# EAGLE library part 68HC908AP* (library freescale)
8-bit microcontroller units (MCUs) low-cost, high-performance M68HC08 Family Source: http://www.freescale.com/files/microcontrollers/doc/data_sheet/MC68HC908AP64.pdf

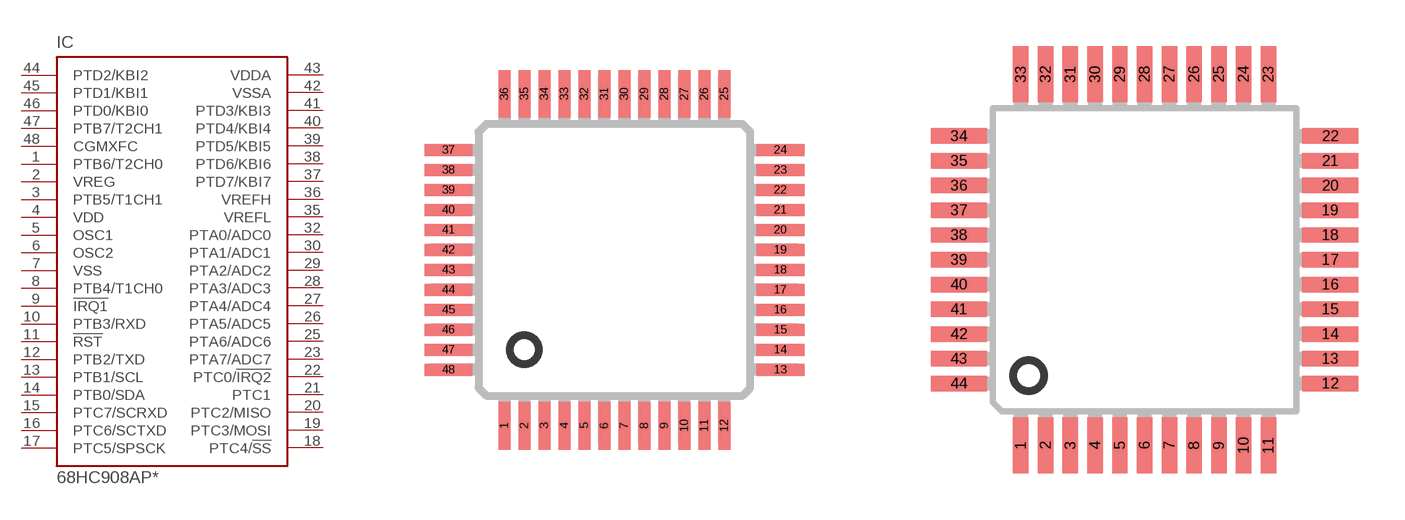
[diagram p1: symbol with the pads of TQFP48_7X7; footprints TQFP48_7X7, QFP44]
Designator prefix IC

## 68HC908AP8CFA (MF: MOTOROLA; MPN: MC68HC908AP8CFA; OC_FARNELL: unknown; OC_NEWARK: 88H9992), 68HC908AP16CFA (MF: MOTOROLA; MPN: MC68HC908AP16CFA; OC_FARNELL: unknown; OC_NEWARK: 88H9989), 68HC908AP32CFA (MF: MOTOROLA; MPN: MC68HC908AP32CFA; OC_FARNELL: unknown; OC_NEWARK: 86H4494), 68HC908AP64CFA (MF: MOTOROLA; MPN: MC68HC908AP64CFA; OC_FARNELL: unknown; OC_NEWARK: 86H4497)  [TQFP48_7X7]
1  PTB6/T2CH0
2  VREG  out
3  PTB5/T1CH1
4  VDD  pwr
5  OSC1  in
6  OSC2  out
7  VSS  pwr
8  PTB4/T1CH0
9  !IRQ1  in
10  PTB3/RXD
11  !RST  in
12  PTB2/TXD
13  PTB1/SCL
14  PTB0/SDA
15  PTC7/SCRXD
16  PTC6/SCTXD
17  PTC5/SPSCK
18  PTC4/!SS
19  PTC3/MOSI
20  PTC2/MISO
21  PTC1
22  PTC0/!IRQ2
23  PTA7/ADC7
25  PTA6/ADC6
26  PTA5/ADC5
27  PTA4/ADC4
28  PTA3/ADC3
29  PTA2/ADC2
30  PTA1/ADC1
32  PTA0/ADC0
35  VREFL  pas
36  VREFH  pas
37  PTD7/KBI7
38  PTD6/KBI6
39  PTD5/KBI5
40  PTD4/KBI4
41  PTD3/KBI3
42  VSSA  pwr
43  VDDA  pwr
44  PTD2/KBI2
45  PTD1/KBI1
46  PTD0/KBI0
47  PTB7/T2CH1
48  CGMXFC  in

## 68HC908AP8CFB (MF: MOTOROLA; MPN: MC68HC908AP8CFB; OC_FARNELL: unknown; OC_NEWARK: 88H9993), 68HC908AP16CFB (MF: MOTOROLA; MPN: MC68HC908AP16CFB; OC_FARNELL: unknown; OC_NEWARK: 88H9990), 68HC908AP23CFB (OC_FARNELL: unknown; OC_NEWARK: unknown), 68HC908AP64CFB (MF: MOTOROLA; MPN: MC68HC908AP64CFB; OC_FARNELL: unknown; OC_NEWARK: 86H4498)  [QFP44]
1  PTB6/T2CH0
2  VREG  out
3  PTB5/T1CH1
4  VDD  pwr
5  OSC1  in
6  OSC2  out
7  VSS  pwr
8  PTB4/T1CH0
9  !IRQ1  in
10  PTB3/RXD
11  !RST  in
12  PTB2/TXD
13  PTB1/SCL
14  PTB0/SDA
15  PTC7/SCRXD
16  PTC6/SCTXD
17  PTC5/SPSCK
18  PTC4/!SS
19  PTC3/MOSI
20  PTC2/MISO
21  PTC1
22  PTC0/!IRQ2
23  PTA7/ADC7
24  PTA6/ADC6
25  PTA5/ADC5
26  PTA4/ADC4
27  PTA3/ADC3
28  PTA2/ADC2
29  PTA1/ADC1
30  PTA0/ADC0
31  VREFL  pas
32  VREFH  pas
33  PTD7/KBI7
34  PTD6/KBI6
35  PTD5/KBI5
36  PTD4/KBI4
37  PTD3/KBI3
38  VSSA  pwr
39  VDDA  pwr
40  PTD2/KBI2
41  PTD1/KBI1
42  PTD0/KBI0
43  PTB7/T2CH1
44  CGMXFC  in

## Footprint TQFP48_7X7 (pad centres in mm)
48-Pin LQFP (Case #932) Source: http://www.freescale.com/files/microcontrollers/doc/data_sheet/MC68HC908AP64.pdf
smd 0.3 x 1.2: 1 -2.75,-4.15; 2 -2.25,-4.15; 3 -1.75,-4.15; 4 -1.25,-4.15; 5 -0.75,-4.15; 6 -0.25,-4.15; 7 0.25,-4.15; 8 0.75,-4.15; 9 1.25,-4.15; 10 1.75,-4.15; 11 2.25,-4.15; 12 2.75,-4.15; 25 2.75,4.15; 26 2.25,4.15; 27 1.75,4.15; 28 1.25,4.15; 29 0.75,4.15; 30 0.25,4.15; 31 -0.25,4.15; 32 -0.75,4.15; 33 -1.25,4.15; 34 -1.75,4.15; 35 -2.25,4.15; 36 -2.75,4.15
smd 1.2 x 0.3: 13 4.15,-2.75; 14 4.15,-2.25; 15 4.15,-1.75; 16 4.15,-1.25; 17 4.15,-0.75; 18 4.15,-0.25; 19 4.15,0.25; 20 4.15,0.75; 21 4.15,1.25; 22 4.15,1.75; 23 4.15,2.25; 24 4.15,2.75; 37 -4.15,2.75; 38 -4.15,2.25; 39 -4.15,1.75; 40 -4.15,1.25; 41 -4.15,0.75; 42 -4.15,0.25; 43 -4.15,-0.25; 44 -4.15,-0.75; 45 -4.15,-1.25; 46 -4.15,-1.75; 47 -4.15,-2.25; 48 -4.15,-2.75

## Footprint QFP44 (pad centres in mm)
44-Pin QFP (Case #824A) Source: http://www.freescale.com/files/microcontrollers/doc/data_sheet/MC68HC908AP64.pdf
smd 0.5 x 1.8: 1 -4,-6; 2 -3.2,-6; 3 -2.4,-6; 4 -1.6,-6; 5 -0.8,-6; 6 0,-6; 7 0.8,-6; 8 1.6,-6; 9 2.4,-6; 10 3.2,-6; 11 4,-6; 23 4,6; 24 3.2,6; 25 2.4,6; 26 1.6,6; 27 0.8,6; 28 0,6; 29 -0.8,6; 30 -1.6,6; 31 -2.4,6; 32 -3.2,6; 33 -4,6
smd 1.8 x 0.5: 12 6,-4; 13 6,-3.2; 14 6,-2.4; 15 6,-1.6; 16 6,-0.8; 17 6,0; 18 6,0.8; 19 6,1.6; 20 6,2.4; 21 6,3.2; 22 6,4; 34 -6,4; 35 -6,3.2; 36 -6,2.4; 37 -6,1.6; 38 -6,0.8; 39 -6,0; 40 -6,-0.8; 41 -6,-1.6; 42 -6,-2.4; 43 -6,-3.2; 44 -6,-4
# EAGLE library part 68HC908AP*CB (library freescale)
8-bit microcontroller units (MCUs) low-cost, high-performance M68HC08 Family Source: http://www.freescale.com/files/microcontrollers/doc/data_sheet/MC68HC908AP64.pdf

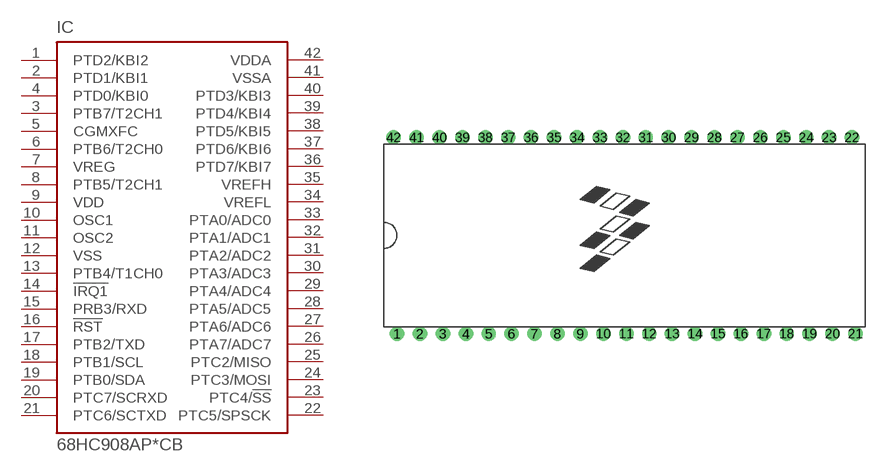
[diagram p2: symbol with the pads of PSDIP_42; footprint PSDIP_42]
Designator prefix IC

## 68HC908AP8CB (MF: MOTOROLA; MPN: MC68HC908AP8CB; OC_FARNELL: unknown; OC_NEWARK: 88H9991), 68HC908AP16CB (MF: MOTOROLA; MPN: MC68HC908AP16CB; OC_FARNELL: unknown; OC_NEWARK: 88H9988), 68HC908AP32CB (MF: MOTOROLA; MPN: MC68HC908AP32CB; OC_FARNELL: unknown; OC_NEWARK: 86H4493), 68HC908AP64CB (MF: MOTOROLA; MPN: MC68HC908AP64CB; OC_FARNELL: unknown; OC_NEWARK: 86H4496)  [PSDIP_42]
1  PTD2/KBI2
2  PTD1/KBI1
3  PTB7/T2CH1
4  PTD0/KBI0
5  CGMXFC  in
6  PTB6/T2CH0
7  VREG  out
8  PTB5/T2CH1
9  VDD  pwr
10  OSC1  in
11  OSC2  out
12  VSS  pwr
13  PTB4/T1CH0
14  !IRQ1  in
15  PRB3/RXD
16  !RST  in
17  PTB2/TXD
18  PTB1/SCL
19  PTB0/SDA
20  PTC7/SCRXD
21  PTC6/SCTXD
22  PTC5/SPSCK
23  PTC4/!SS
24  PTC3/MOSI
25  PTC2/MISO
26  PTA7/ADC7
27  PTA6/ADC6
28  PTA5/ADC5
29  PTA4/ADC4
30  PTA3/ADC3
31  PTA2/ADC2
32  PTA1/ADC1
33  PTA0/ADC0
34  VREFL  pas
35  VREFH  pas
36  PTD7/KBI7
37  PTD6/KBI6
38  PTD5/KBI5
39  PTD4/KBI4
40  PTD3/KBI3
41  VSSA  pwr
42  VDDA  pwr

## Footprint PSDIP_42 (pad centres in mm)
42-Pin Shrink Dual In-Line Package (SDIP) Case #858 Source: http://www.freescale.com/files/microcontrollers/doc/data_sheet/MC68HC908AP64.pdf
drill 0.61 pad 1.016 round: 1 -17.78,-7.62; 2 -16.002,-7.62; 3 -14.224,-7.62; 4 -12.446,-7.62; 5 -10.668,-7.62; 6 -8.89,-7.62; 7 -7.112,-7.62; 8 -5.334,-7.62; 9 -3.556,-7.62; 10 -1.778,-7.62; 11 0,-7.62; 12 1.778,-7.62; 13 3.556,-7.62; 14 5.334,-7.62; 15 7.112,-7.62; 16 8.89,-7.62; 17 10.668,-7.62; 18 12.446,-7.62; 19 14.224,-7.62; 20 16.002,-7.62; 21 17.78,-7.62; 22 17.513,7.62; 23 15.735,7.62; 24 13.957,7.62; 25 12.179,7.62; 26 10.401,7.62; 27 8.623,7.62; 28 6.845,7.62; 29 5.067,7.62; 30 3.289,7.62; 31 1.511,7.62; 32 -0.267,7.62; 33 -2.045,7.62; 34 -3.823,7.62; 35 -5.601,7.62; 36 -7.379,7.62; 37 -9.157,7.62; 38 -10.935,7.62; 39 -12.713,7.62; 40 -14.491,7.62; 41 -16.269,7.62; 42 -18.047,7.62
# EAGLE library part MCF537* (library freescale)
MCF537x ColdFire® Microprocessor Source: www.freescale.com .. MCF5373DS.pdf

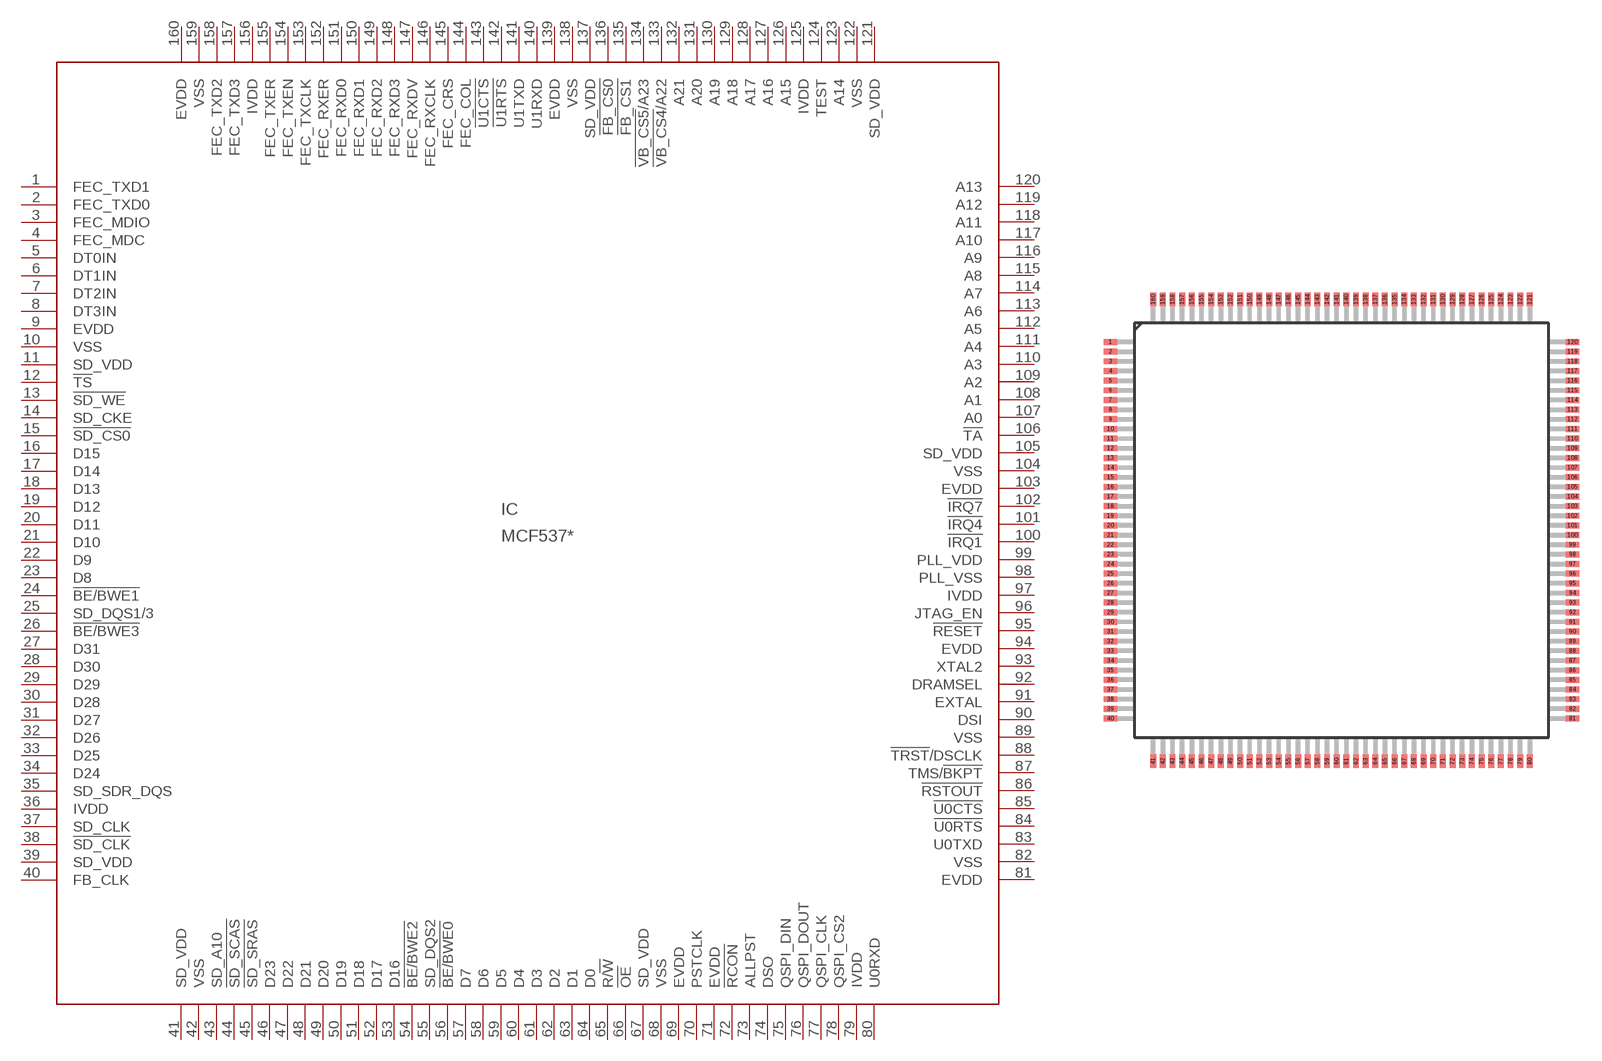
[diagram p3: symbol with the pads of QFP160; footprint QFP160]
Designator prefix IC

## MCF5372 (OC_FARNELL: unknown; OC_NEWARK: unknown), MCF5373 (OC_FARNELL: unknown; OC_NEWARK: unknown)  [QFP160]
1  FEC_TXD1  out
2  FEC_TXD0  out
3  FEC_MDIO
4  FEC_MDC  out
5  DT0IN  in
6  DT1IN  in
7  DT2IN  in
8  DT3IN  in
9  EVDD  pwr
10  VSS  pwr
11  SD_VDD  pwr
12  !TS  out
13  !SD_WE  out
14  SD_CKE  out
15  !SD_CS0  out
16  D15
17  D14
18  D13
19  D12
20  D11
21  D10
22  D9
23  D8
24  !BE/BWE1  out
25  SD_DQS1/3  out
26  !BE/BWE3  out
27  D31
28  D30
29  D29
30  D28
31  D27
32  D26
33  D25
34  D24
35  SD_SDR_DQS  out
36  IVDD  pwr
37  SD_CLK  out
38  !SD_CLK  out
39  SD_VDD  pwr
40  FB_CLK  out
41  SD_VDD  pwr
42  VSS  pwr
43  SD_A10  out
44  !SD_SCAS  out
45  !SD_SRAS  out
46  D23
47  D22
48  D21
49  D20
50  D19
51  D18
52  D17
53  D16
54  !BE/BWE2  out
55  SD_DQS2  out
56  !BE/BWE0  out
57  D7
58  D6
59  D5
60  D4
61  D3
62  D2
63  D1
64  D0
65  R/!W  out
66  !OE  out
67  SD_VDD  pwr
68  VSS  pwr
69  EVDD  pwr
70  PSTCLK  out
71  EVDD  pwr
72  !RCON  in
73  ALLPST  out
74  DSO  out
75  QSPI_DIN  in
76  QSPI_DOUT  out
77  QSPI_CLK  out
78  QSPI_CS2  out
79  IVDD  pwr
80  U0RXD  in
81  EVDD  pwr
82  VSS  pwr
83  U0TXD  out
84  !U0RTS  out
85  !U0CTS  in
86  !RSTOUT  out
87  TMS/!BKPT  in
88  !TRST!/DSCLK  in
89  VSS  pwr
90  DSI  in
91  EXTAL  in
92  DRAMSEL  in
93  XTAL2  out
94  EVDD  pwr
95  !RESET  in
96  JTAG_EN  in
97  IVDD  pwr
98  PLL_VSS  pwr
99  PLL_VDD  pwr
100  !IRQ1  in
101  !IRQ4  in
102  !IRQ7  in
103  EVDD  pwr
104  VSS  pwr
105  SD_VDD  pwr
106  !TA  in
107  A0  out
108  A1  out
109  A2  out
110  A3  out
111  A4  out
112  A5  out
113  A6  out
114  A7  out
115  A8  out
116  A9  out
117  A10  out
118  A11  out
119  A12  out
120  A13  out
121  SD_VDD  pwr
122  VSS  pwr
123  A14  out
124  TEST  in
125  IVDD  pwr
126  A15  out
127  A16  out
128  A17  out
129  A18  out
130  A19  out
131  A20  out
132  A21  out
133  !VB_CS4!/A22  out
134  !VB_CS5!/A23  out
135  !FB_CS1  out
136  !FB_CS0  out
137  SD_VDD  pwr
138  VSS  pwr
139  EVDD  pwr
140  U1RXD  in
141  U1TXD  out
142  !U1RTS  out
143  !U1CTS  in
144  FEC_COL  in
145  FEC_CRS  in
146  FEC_RXCLK  in
147  FEC_RXDV  in
148  FEC_RXD3  in
149  FEC_RXD2  in
150  FEC_RXD1  in
151  FEC_RXD0  in
152  FEC_RXER  in
153  FEC_TXCLK  in
154  FEC_TXEN  out
155  FEC_TXER  out
156  IVDD  pwr
157  FEC_TXD3  out
158  FEC_TXD2  out
159  VSS  pwr
160  EVDD  pwr

## Footprint QFP160 (pad centres in mm)
QFP160 Auto generated by make-symbol-device-package-bsdl.ulp Rev. 22
smd 0.9 x 0.4: 1 -15.55,12.675; 2 -15.55,12.025; 3 -15.55,11.375; 4 -15.55,10.725; 5 -15.55,10.075; 6 -15.55,9.425; 7 -15.55,8.775; 8 -15.55,8.125; 9 -15.55,7.475; 10 -15.55,6.825; 11 -15.55,6.175; 12 -15.55,5.525; 13 -15.55,4.875; 14 -15.55,4.225; 15 -15.55,3.575; 16 -15.55,2.925; 17 -15.55,2.275; 18 -15.55,1.625; 19 -15.55,0.975; 20 -15.55,0.325; 21 -15.55,-0.325; 22 -15.55,-0.975; 23 -15.55,-1.625; 24 -15.55,-2.275; 25 -15.55,-2.925; 26 -15.55,-3.575; 27 -15.55,-4.225; 28 -15.55,-4.875; 29 -15.55,-5.525; 30 -15.55,-6.175; 31 -15.55,-6.825; 32 -15.55,-7.475; 33 -15.55,-8.125; 34 -15.55,-8.775; 35 -15.55,-9.425; 36 -15.55,-10.075; 37 -15.55,-10.725; 38 -15.55,-11.375; 39 -15.55,-12.025; 40 -15.55,-12.675; 81 15.55,-12.675; 82 15.55,-12.025; 83 15.55,-11.375; 84 15.55,-10.725; 85 15.55,-10.075; 86 15.55,-9.425; 87 15.55,-8.775; 88 15.55,-8.125; 89 15.55,-7.475; 90 15.55,-6.825; 91 15.55,-6.175; 92 15.55,-5.525; 93 15.55,-4.875; 94 15.55,-4.225; 95 15.55,-3.575; 96 15.55,-2.925; 97 15.55,-2.275; 98 15.55,-1.625; 99 15.55,-0.975; 100 15.55,-0.325; 101 15.55,0.325; 102 15.55,0.975; 103 15.55,1.625; 104 15.55,2.275; 105 15.55,2.925; 106 15.55,3.575; 107 15.55,4.225; 108 15.55,4.875; 109 15.55,5.525; 110 15.55,6.175; 111 15.55,6.825; 112 15.55,7.475; 113 15.55,8.125; 114 15.55,8.775; 115 15.55,9.425; 116 15.55,10.075; 117 15.55,10.725; 118 15.55,11.375; 119 15.55,12.025; 120 15.55,12.675
smd 0.4 x 0.9: 41 -12.675,-15.55; 42 -12.025,-15.55; 43 -11.375,-15.55; 44 -10.725,-15.55; 45 -10.075,-15.55; 46 -9.425,-15.55; 47 -8.775,-15.55; 48 -8.125,-15.55; 49 -7.475,-15.55; 50 -6.825,-15.55; 51 -6.175,-15.55; 52 -5.525,-15.55; 53 -4.875,-15.55; 54 -4.225,-15.55; 55 -3.575,-15.55; 56 -2.925,-15.55; 57 -2.275,-15.55; 58 -1.625,-15.55; 59 -0.975,-15.55; 60 -0.325,-15.55; 61 0.325,-15.55; 62 0.975,-15.55; 63 1.625,-15.55; 64 2.275,-15.55; 65 2.925,-15.55; 66 3.575,-15.55; 67 4.225,-15.55; 68 4.875,-15.55; 69 5.525,-15.55; 70 6.175,-15.55; 71 6.825,-15.55; 72 7.475,-15.55; 73 8.125,-15.55; 74 8.775,-15.55; 75 9.425,-15.55; 76 10.075,-15.55; 77 10.725,-15.55; 78 11.375,-15.55; 79 12.025,-15.55; 80 12.675,-15.55; 121 12.675,15.55; 122 12.025,15.55; 123 11.375,15.55; 124 10.725,15.55; 125 10.075,15.55; 126 9.425,15.55; 127 8.775,15.55; 128 8.125,15.55; 129 7.475,15.55; 130 6.825,15.55; 131 6.175,15.55; 132 5.525,15.55; 133 4.875,15.55; 134 4.225,15.55; 135 3.575,15.55; 136 2.925,15.55; 137 2.275,15.55; 138 1.625,15.55; 139 0.975,15.55; 140 0.325,15.55; 141 -0.325,15.55; 142 -0.975,15.55; 143 -1.625,15.55; 144 -2.275,15.55; 145 -2.925,15.55; 146 -3.575,15.55; 147 -4.225,15.55; 148 -4.875,15.55; 149 -5.525,15.55; 150 -6.175,15.55; 151 -6.825,15.55; 152 -7.475,15.55; 153 -8.125,15.55; 154 -8.775,15.55; 155 -9.425,15.55; 156 -10.075,15.55; 157 -10.725,15.55; 158 -11.375,15.55; 159 -12.025,15.55; 160 -12.675,15.55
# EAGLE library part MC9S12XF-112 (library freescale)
MC9S12XF512 Source: www.freescale.com .. MC9S12XF512V1RM.pdf

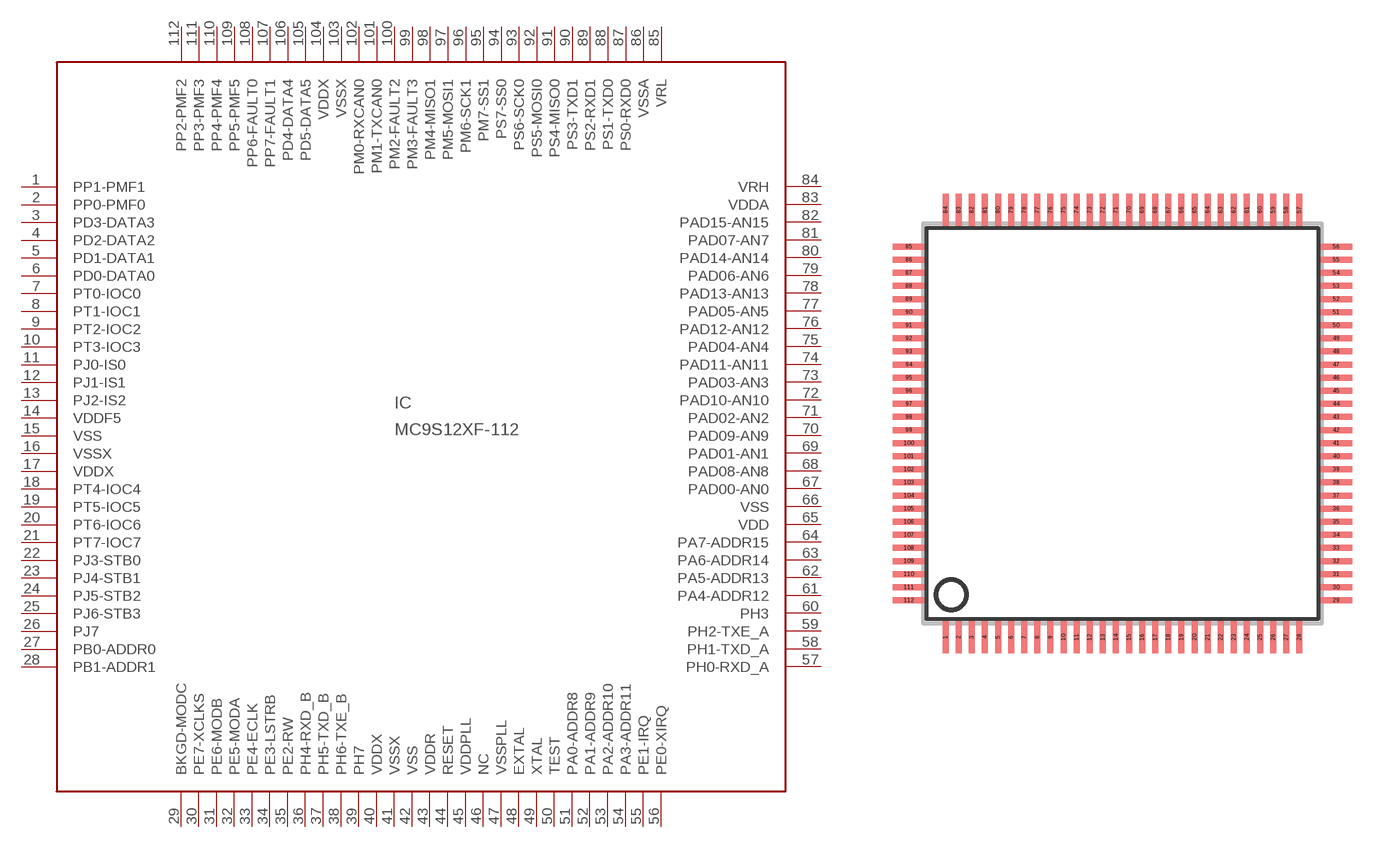
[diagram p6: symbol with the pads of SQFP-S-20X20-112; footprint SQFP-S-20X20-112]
Designator prefix IC

## MC9S12XF-112 (OC_FARNELL: unknown; OC_NEWARK: unknown)  [SQFP-S-20X20-112]
1  PP1-PMF1
2  PP0-PMF0
3  PD3-DATA3
4  PD2-DATA2
5  PD1-DATA1
6  PD0-DATA0
7  PT0-IOC0
8  PT1-IOC1
9  PT2-IOC2
10  PT3-IOC3
11  PJ0-IS0
12  PJ1-IS1
13  PJ2-IS2
14  VDDF5  pwr
15  VSS  pwr
16  VSSX  pwr
17  VDDX  pwr
18  PT4-IOC4
19  PT5-IOC5
20  PT6-IOC6
21  PT7-IOC7
22  PJ3-STB0
23  PJ4-STB1
24  PJ5-STB2
25  PJ6-STB3
26  PJ7
27  PB0-ADDR0
28  PB1-ADDR1
29  BKGD-MODC
30  PE7-XCLKS
31  PE6-MODB
32  PE5-MODA
33  PE4-ECLK
34  PE3-LSTRB
35  PE2-RW
36  PH4-RXD_B
37  PH5-TXD_B
38  PH6-TXE_B
39  PH7
40  VDDX  pwr
41  VSSX  pwr
42  VSS  pwr
43  VDDR  pwr
44  RESET
45  VDDPLL  pwr
46  NC  nc
47  VSSPLL  pwr
48  EXTAL  pas
49  XTAL  pas
50  TEST  in
51  PA0-ADDR8
52  PA1-ADDR9
53  PA2-ADDR10
54  PA3-ADDR11
55  PE1-IRQ  in
56  PE0-XIRQ  in
57  PH0-RXD_A
58  PH1-TXD_A
59  PH2-TXE_A
60  PH3
61  PA4-ADDR12
62  PA5-ADDR13
63  PA6-ADDR14
64  PA7-ADDR15
65  VDD  pwr
66  VSS  pwr
67  PAD00-AN0
68  PAD08-AN8
69  PAD01-AN1
70  PAD09-AN9
71  PAD02-AN2
72  PAD10-AN10
73  PAD03-AN3
74  PAD11-AN11
75  PAD04-AN4
76  PAD12-AN12
77  PAD05-AN5
78  PAD13-AN13
79  PAD06-AN6
80  PAD14-AN14
81  PAD07-AN7
82  PAD15-AN15
83  VDDA  pwr
84  VRH  pwr
85  VRL  pwr
86  VSSA  pwr
87  PS0-RXD0
88  PS1-TXD0
89  PS2-RXD1
90  PS3-TXD1
91  PS4-MISO0
92  PS5-MOSI0
93  PS6-SCK0
94  PS7-SS0
95  PM7-SS1
96  PM6-SCK1
97  PM5-MOSI1
98  PM4-MISO1
99  PM3-FAULT3
100  PM2-FAULT2
101  PM1-TXCAN0
102  PM0-RXCAN0
103  VSSX  pwr
104  VDDX  pwr
105  PD5-DATA5
106  PD4-DATA4
107  PP7-FAULT1
108  PP6-FAULT0
109  PP5-PMF5
110  PP4-PMF4
111  PP3-PMF3
112  PP2-PMF2

## Footprint SQFP-S-20X20-112 (pad centres in mm)
LQFP112 20x20mm 112-Pin LQFP Mechanical Dimensions (Case No. 987) Source: www.freescale.com .. MC9S12XF512V1RM.pdf
smd 0.3 x 1.6: 1 -8.775,-10.6; 2 -8.125,-10.6; 3 -7.475,-10.6; 4 -6.825,-10.6; 5 -6.175,-10.6; 6 -5.525,-10.6; 7 -4.875,-10.6; 8 -4.225,-10.6; 9 -3.575,-10.6; 10 -2.925,-10.6; 11 -2.275,-10.6; 12 -1.625,-10.6; 13 -0.975,-10.6; 14 -0.325,-10.6; 15 0.325,-10.6; 16 0.975,-10.6; 17 1.625,-10.6; 18 2.275,-10.6; 19 2.925,-10.6; 20 3.575,-10.6; 21 4.225,-10.6; 22 4.875,-10.6; 23 5.525,-10.6; 24 6.175,-10.6; 25 6.825,-10.6; 26 7.475,-10.6; 27 8.125,-10.6; 28 8.775,-10.6; 57 8.775,10.6; 58 8.125,10.6; 59 7.475,10.6; 60 6.825,10.6; 61 6.175,10.6; 62 5.525,10.6; 63 4.875,10.6; 64 4.225,10.6; 65 3.575,10.6; 66 2.925,10.6; 67 2.275,10.6; 68 1.625,10.6; 69 0.975,10.6; 70 0.325,10.6; 71 -0.325,10.6; 72 -0.975,10.6; 73 -1.625,10.6; 74 -2.275,10.6; 75 -2.925,10.6; 76 -3.575,10.6; 77 -4.225,10.6; 78 -4.875,10.6; 79 -5.525,10.6; 80 -6.175,10.6; 81 -6.825,10.6; 82 -7.475,10.6; 83 -8.125,10.6; 84 -8.775,10.6
smd 1.6 x 0.3: 29 10.6,-8.775; 30 10.6,-8.125; 31 10.6,-7.475; 32 10.6,-6.825; 33 10.6,-6.175; 34 10.6,-5.525; 35 10.6,-4.875; 36 10.6,-4.225; 37 10.6,-3.575; 38 10.6,-2.925; 39 10.6,-2.275; 40 10.6,-1.625; 41 10.6,-0.975; 42 10.6,-0.325; 43 10.6,0.325; 44 10.6,0.975; 45 10.6,1.625; 46 10.6,2.275; 47 10.6,2.925; 48 10.6,3.575; 49 10.6,4.225; 50 10.6,4.875; 51 10.6,5.525; 52 10.6,6.175; 53 10.6,6.825; 54 10.6,7.475; 55 10.6,8.125; 56 10.6,8.775; 85 -10.6,8.775; 86 -10.6,8.125; 87 -10.6,7.475; 88 -10.6,6.825; 89 -10.6,6.175; 90 -10.6,5.525; 91 -10.6,4.875; 92 -10.6,4.225; 93 -10.6,3.575; 94 -10.6,2.925; 95 -10.6,2.275; 96 -10.6,1.625; 97 -10.6,0.975; 98 -10.6,0.325; 99 -10.6,-0.325; 100 -10.6,-0.975; 101 -10.6,-1.625; 102 -10.6,-2.275; 103 -10.6,-2.925; 104 -10.6,-3.575; 105 -10.6,-4.225; 106 -10.6,-4.875; 107 -10.6,-5.525; 108 -10.6,-6.175; 109 -10.6,-6.825; 110 -10.6,-7.475; 111 -10.6,-8.125; 112 -10.6,-8.775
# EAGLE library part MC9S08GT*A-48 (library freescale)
HCS08 Microcontroller Source: http://www.freescale.com/files/microcontrollers/doc/data_sheet/MC9S08GT16A.pdf

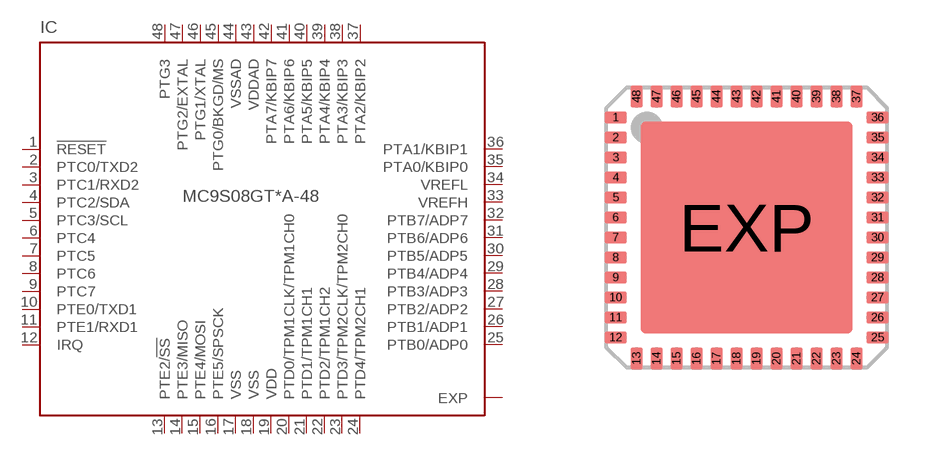
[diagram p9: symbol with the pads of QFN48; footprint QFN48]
Designator prefix IC

## MC9S08GT8A-48 (MF: MOTOROLA; MPN: MC9S08GT8AMFDE; OC_FARNELL: 1294360; OC_NEWARK: 01M5874), MC9S08GT16A-48 (MF: MOTOROLA; MPN: MC9S08GT16ACFDE; OC_FARNELL: 1579705; OC_NEWARK: 01M5861)  [QFN48]
1  !RESET  in
2  PTC0/TXD2
3  PTC1/RXD2
4  PTC2/SDA
5  PTC3/SCL
6  PTC4
7  PTC5
8  PTC6
9  PTC7
10  PTE0/TXD1
11  PTE1/RXD1
12  IRQ
13  PTE2/!SS
14  PTE3/MISO
15  PTE4/MOSI
16  PTE5/SPSCK
17  VSS  pwr
18  VSS  pwr
19  VDD  pwr
20  PTD0/TPM1CLK/TPM1CH0
21  PTD1/TPM1CH1
22  PTD2/TPM1CH2
23  PTD3/TPM2CLK/TPM2CH0
24  PTD4/TPM2CH1
25  PTB0/ADP0
26  PTB1/ADP1
27  PTB2/ADP2
28  PTB3/ADP3
29  PTB4/ADP4
30  PTB5/ADP5
31  PTB6/ADP6
32  PTB7/ADP7
33  VREFH
34  VREFL
35  PTA0/KBIP0
36  PTA1/KBIP1
37  PTA2/KBIP2
38  PTA3/KBIP3
39  PTA4/KBIP4
40  PTA5/KBIP5
41  PTA6/KBIP6
42  PTA7/KBIP7
43  VDDAD  pwr
44  VSSAD  pwr
45  PTG0/BKGD/MS
46  PTG1/XTAL
47  PTG2/EXTAL
48  PTG3
EXP  EXP  pas

## Footprint QFN48 (pad centres in mm)
48-pin QFN 7 x 7 mm LF48 48 Quad Flat Package No Leads Source: http://v4.cypress.com/cfuploads/img/products/cywusb6934.pdf
smd 0.55 x 0.3: 1 -3.275,2.75; 2 -3.275,2.25; 3 -3.275,1.75; 4 -3.275,1.25; 5 -3.275,0.75; 6 -3.275,0.25; 7 -3.275,-0.25; 8 -3.275,-0.75; 9 -3.275,-1.25; 10 -3.275,-1.75; 11 -3.275,-2.25; 12 -3.275,-2.75; 25 3.275,-2.75; 26 3.275,-2.25; 27 3.275,-1.75; 28 3.275,-1.25; 29 3.275,-0.75; 30 3.275,-0.25; 31 3.275,0.25; 32 3.275,0.75; 33 3.275,1.25; 34 3.275,1.75; 35 3.275,2.25; 36 3.275,2.75
smd 0.3 x 0.55: 13 -2.75,-3.275; 14 -2.25,-3.275; 15 -1.75,-3.275; 16 -1.25,-3.275; 17 -0.75,-3.275; 18 -0.25,-3.275; 19 0.25,-3.275; 20 0.75,-3.275; 21 1.25,-3.275; 22 1.75,-3.275; 23 2.25,-3.275; 24 2.75,-3.275; 37 2.75,3.275; 38 2.25,3.275; 39 1.75,3.275; 40 1.25,3.275; 41 0.75,3.275; 42 0.25,3.275; 43 -0.25,3.275; 44 -0.75,3.275; 45 -1.25,3.275; 46 -1.75,3.275; 47 -2.25,3.275; 48 -2.75,3.275
smd 5.309 x 5.309: EXP 0,0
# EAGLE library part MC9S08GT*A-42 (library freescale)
HCS08 Microcontroller Source: http://www.freescale.com/files/microcontrollers/doc/data_sheet/MC9S08GT16A.pdf

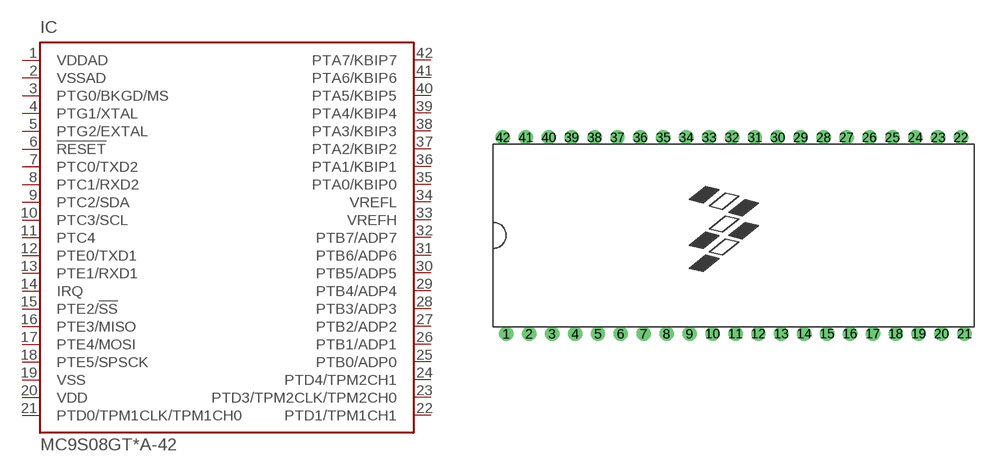
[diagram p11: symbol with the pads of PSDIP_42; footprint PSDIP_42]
Designator prefix IC

## MC9S08GT8A-42 (MF: MOTOROLA; MPN: MC9S08GT8ACBE; OC_FARNELL: 1294366; OC_NEWARK: 01M5868), MC9S08GT16A-42 (MF: MOTOROLA; MPN: MC9S08GT16ACBE; OC_FARNELL: unknown; OC_NEWARK: 01M5858)  [PSDIP_42]
1  VDDAD  pwr
2  VSSAD  pwr
3  PTG0/BKGD/MS
4  PTG1/XTAL
5  PTG2/EXTAL
6  !RESET  in
7  PTC0/TXD2
8  PTC1/RXD2
9  PTC2/SDA
10  PTC3/SCL
11  PTC4
12  PTE0/TXD1
13  PTE1/RXD1
14  IRQ
15  PTE2/!SS
16  PTE3/MISO
17  PTE4/MOSI
18  PTE5/SPSCK
19  VSS  pwr
20  VDD  pwr
21  PTD0/TPM1CLK/TPM1CH0
22  PTD1/TPM1CH1
23  PTD3/TPM2CLK/TPM2CH0
24  PTD4/TPM2CH1
25  PTB0/ADP0
26  PTB1/ADP1
27  PTB2/ADP2
28  PTB3/ADP3
29  PTB4/ADP4
30  PTB5/ADP5
31  PTB6/ADP6
32  PTB7/ADP7
33  VREFH
34  VREFL
35  PTA0/KBIP0
36  PTA1/KBIP1
37  PTA2/KBIP2
38  PTA3/KBIP3
39  PTA4/KBIP4
40  PTA5/KBIP5
41  PTA6/KBIP6
42  PTA7/KBIP7

## Footprint PSDIP_42 (pad centres in mm)
42-Pin Shrink Dual In-Line Package (SDIP) Case #858 Source: http://www.freescale.com/files/microcontrollers/doc/data_sheet/MC68HC908AP64.pdf
drill 0.61 pad 1.016 round: 1 -17.78,-7.62; 2 -16.002,-7.62; 3 -14.224,-7.62; 4 -12.446,-7.62; 5 -10.668,-7.62; 6 -8.89,-7.62; 7 -7.112,-7.62; 8 -5.334,-7.62; 9 -3.556,-7.62; 10 -1.778,-7.62; 11 0,-7.62; 12 1.778,-7.62; 13 3.556,-7.62; 14 5.334,-7.62; 15 7.112,-7.62; 16 8.89,-7.62; 17 10.668,-7.62; 18 12.446,-7.62; 19 14.224,-7.62; 20 16.002,-7.62; 21 17.78,-7.62; 22 17.513,7.62; 23 15.735,7.62; 24 13.957,7.62; 25 12.179,7.62; 26 10.401,7.62; 27 8.623,7.62; 28 6.845,7.62; 29 5.067,7.62; 30 3.289,7.62; 31 1.511,7.62; 32 -0.267,7.62; 33 -2.045,7.62; 34 -3.823,7.62; 35 -5.601,7.62; 36 -7.379,7.62; 37 -9.157,7.62; 38 -10.935,7.62; 39 -12.713,7.62; 40 -14.491,7.62; 41 -16.269,7.62; 42 -18.047,7.62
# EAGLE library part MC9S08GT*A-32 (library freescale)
HCS08 Microcontroller Source: http://www.freescale.com/files/microcontrollers/doc/data_sheet/MC9S08GT16A.pdf

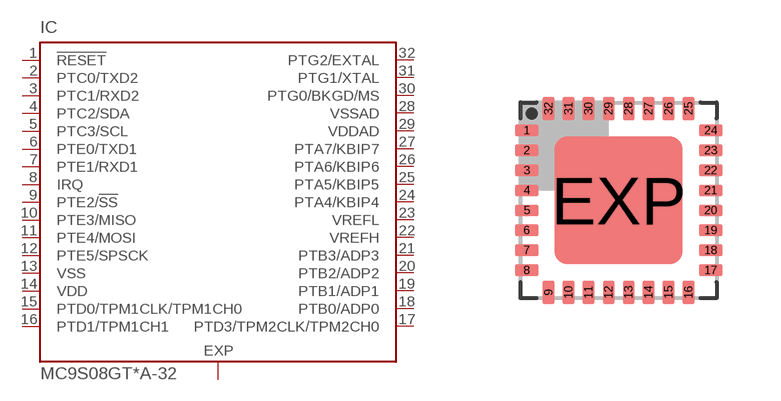
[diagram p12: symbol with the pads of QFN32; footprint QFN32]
Designator prefix IC

## MC9S08GT8A-32 (MF: MOTOROLA; MPN: MC9S08GT8AMFCE; OC_FARNELL: 1294367; OC_NEWARK: 01M5873), MC9S08GT16A-32 (MF: MOTOROLA; MPN: MC9S08GT16ACFCE; OC_FARNELL: unknown; OC_NEWARK: 01M5860)  [QFN32]
1  !RESET  in
2  PTC0/TXD2
3  PTC1/RXD2
4  PTC2/SDA
5  PTC3/SCL
6  PTE0/TXD1
7  PTE1/RXD1
8  IRQ
9  PTE2/!SS
10  PTE3/MISO
11  PTE4/MOSI
12  PTE5/SPSCK
13  VSS  pwr
14  VDD  pwr
15  PTD0/TPM1CLK/TPM1CH0
16  PTD1/TPM1CH1
17  PTD3/TPM2CLK/TPM2CH0
18  PTB0/ADP0
19  PTB1/ADP1
20  PTB2/ADP2
21  PTB3/ADP3
22  VREFH
23  VREFL
24  PTA4/KBIP4
25  PTA5/KBIP5
26  PTA6/KBIP6
27  PTA7/KBIP7
28  VSSAD  pwr
29  VDDAD  pwr
30  PTG0/BKGD/MS
31  PTG1/XTAL
32  PTG2/EXTAL
EXP  EXP  pas

## Footprint QFN32 (pad centres in mm)
QFN 32 5 x 5 mm Source: http://datasheets.maxim-ic.com/en/ds/MAX7042.pdf
smd 0.6 x 0.3: 1 -2.3,1.75; 2 -2.3,1.25; 3 -2.3,0.75; 4 -2.3,0.25; 5 -2.3,-0.25; 6 -2.3,-0.75; 7 -2.3,-1.25; 8 -2.3,-1.75; 17 2.3,-1.75; 18 2.3,-1.25; 19 2.3,-0.75; 20 2.3,-0.25; 21 2.3,0.25; 22 2.3,0.75; 23 2.3,1.25; 24 2.3,1.75
smd 0.3 x 0.6: 9 -1.75,-2.3; 10 -1.25,-2.3; 11 -0.75,-2.3; 12 -0.25,-2.3; 13 0.25,-2.3; 14 0.75,-2.3; 15 1.25,-2.3; 16 1.75,-2.3; 25 1.75,2.3; 26 1.25,2.3; 27 0.75,2.3; 28 0.25,2.3; 29 -0.25,2.3; 30 -0.75,2.3; 31 -1.25,2.3; 32 -1.75,2.3
smd 3.2 x 3.2: EXP 0,0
